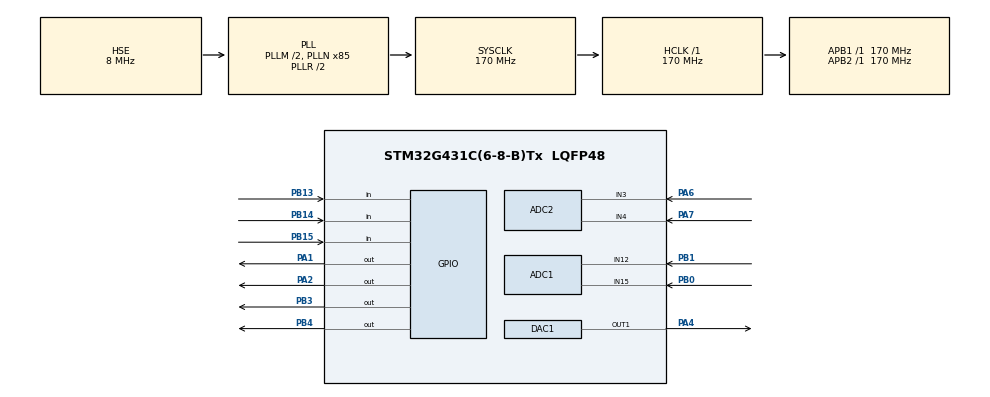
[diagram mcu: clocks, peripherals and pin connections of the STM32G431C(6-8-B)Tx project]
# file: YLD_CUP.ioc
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ADC1.Channel-1\#ChannelRegularConversion=ADC_CHANNEL_15
ADC1.ClockPrescaler=ADC_CLOCK_ASYNC_DIV8
ADC1.NbrOfConversionFlag=1
ADC1.OffsetNumber-1\#ChannelRegularConversion=ADC_OFFSET_NONE
ADC1.Rank-1\#ChannelRegularConversion=1
ADC1.SamplingTime-1\#ChannelRegularConversion=ADC_SAMPLETIME_640CYCLES_5
ADC1.master=1
ADC2.Channel-1\#ChannelRegularConversion=ADC_CHANNEL_3
ADC2.ClockPrescaler=ADC_CLOCK_ASYNC_DIV8
ADC2.NbrOfConversionFlag=1
ADC2.OffsetNumber-1\#ChannelRegularConversion=ADC_OFFSET_NONE
ADC2.Rank-1\#ChannelRegularConversion=1
ADC2.SamplingTime-1\#ChannelRegularConversion=ADC_SAMPLETIME_640CYCLES_5
Mcu.Family=STM32G4
Mcu.Name=STM32G431C(6-8-B)Tx
Mcu.Package=LQFP48
NVIC.PriorityGroup=NVIC_PRIORITYGROUP_4
PA1.Signal=GPIO_Output
PA13.Mode=Serial_Wire
PA13.Signal=SYS_JTMS-SWDIO
PA14.Mode=Serial_Wire
PA14.Signal=SYS_JTCK-SWCLK
PA2.Signal=GPIO_Output
PA4.Signal=COMP_DAC11_group
PA6.Mode=IN3-Single-Ended
PA6.Signal=ADC2_IN3
PA7.Mode=IN4-Single-Ended
PA7.Signal=ADC2_IN4
PB0.Mode=IN15-Single-Ended
PB0.Signal=ADC1_IN15
PB1.Mode=IN12-Single-Ended
PB1.Signal=ADC1_IN12
PB13.GPIO_PuPd=GPIO_PULLUP
PB13.Signal=GPIO_Input
PB14.GPIO_PuPd=GPIO_PULLUP
PB14.Signal=GPIO_Input
PB15.GPIO_PuPd=GPIO_PULLUP
PB15.Signal=GPIO_Input
PB3.GPIO_ModeDefaultOutputPP=GPIO_MODE_OUTPUT_OD
PB3.GPIO_PuPd=GPIO_NOPULL
PB3.GPIO_Speed=GPIO_SPEED_FREQ_HIGH
PB3.PinState=GPIO_PIN_SET
PB3.Signal=GPIO_Output
PB4.GPIO_ModeDefaultOutputPP=GPIO_MODE_OUTPUT_OD
PB4.GPIO_PuPd=GPIO_NOPULL
PB4.GPIO_Speed=GPIO_SPEED_FREQ_HIGH
PB4.PinState=GPIO_PIN_SET
PB4.Signal=GPIO_Output
PF0-OSC_IN.Mode=HSE-External-Oscillator
PF0-OSC_IN.Signal=RCC_OSC_IN
PF1-OSC_OUT.Mode=HSE-External-Oscillator
PF1-OSC_OUT.Signal=RCC_OSC_OUT
ProjectManager.HeapSize=0x200
ProjectManager.StackSize=0x400
ProjectManager.TargetToolchain=CMake
RCC.ADC12Freq_Value=170000000
RCC.AHBFreq_Value=170000000
RCC.APB1Freq_Value=170000000
RCC.APB1TimFreq_Value=170000000
RCC.APB2Freq_Value=170000000
RCC.APB2TimFreq_Value=170000000
RCC.CortexFreq_Value=170000000
RCC.EXTERNAL_CLOCK_VALUE=12288000
RCC.HCLKFreq_Value=170000000
RCC.HSI48_VALUE=48000000
RCC.HSI_VALUE=16000000
RCC.LSE_VALUE=32768
RCC.PLLM=RCC_PLLM_DIV2
RCC.PLLN=85
RCC.PLLSourceVirtual=RCC_PLLSOURCE_HSE
RCC.SYSCLKFreq_VALUE=170000000
RCC.SYSCLKSource=RCC_SYSCLKSOURCE_PLLCLK
RCC.USBFreq_Value=170000000
RCC.VCOOutputFreq_Value=340000000
SH.COMP_DAC11_group.0=DAC1_OUT1,DAC_OUT1
VP_SYS_VS_DBSignals.Mode=DisableDeadBatterySignals
board=custom

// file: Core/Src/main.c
/* USER CODE BEGIN Header */
/**
  ******************************************************************************
  * @file           : main.c
  * @brief          : Main program body
  ******************************************************************************
  * @attention
  *
  * Copyright (c) 2026 STMicroelectronics.
  * All rights reserved.
  *
  * This software is licensed under terms that can be found in the LICENSE file
  * in the root directory of this software component.
  * If no LICENSE file comes with this software, it is provided AS-IS.
  *
  ******************************************************************************
  */
/* USER CODE END Header */
#include "main.h"

/* USER CODE BEGIN Includes */
#include "OLED.h"
#include "buzzer.h"
#include "measurement_calibration.h"
#include <math.h>
/* USER CODE END Includes */

/* USER CODE BEGIN PTD */
/* 应用状态机 (题目 1.1 / 1.2 / 2.1 + 恒流模式) */
typedef enum
{
  APP_ST_SELF_TEST = 0,   /* 开机自检 (蜂鸣 3 声) */
  APP_ST_STANDBY,         /* 待机: 无输出 */
  APP_ST_CV,              /* 恒压模式 */
  APP_ST_CC,              /* 恒流模式 */
  APP_ST_PROT_OCP,        /* 过流保护: 关输出 + 报警, 手动解除 */
  APP_ST_PROT_UVP,        /* 欠压保护: 关输出 + 报警, 手动忽略后恢复 */
  APP_ST_PROT_ADC,        /* 采样故障: 关输出 + 报警, 手动重试后回待机 */
} AppState_t;

/* 按键事件 */
typedef enum
{
  KEY_EV_NONE = 0,
  KEY_EV_SHORT,           /* 短按 (松手时产生) */
  KEY_EV_LONG,            /* 长按 (按住超过 KEY_LONG_MS, 只产生一次) */
} KeyEvent_t;

/* 按键对象 */
typedef struct
{
  GPIO_TypeDef *port;
  uint16_t      pin;
  uint8_t       stable;     /* 消抖后的稳定电平: 1=松开, 0=按下 */
  uint8_t       rawLast;    /* 上一次原始电平 */
  uint32_t      changedAt;  /* 原始电平改变的时刻 */
  uint32_t      pressedAt;  /* 消抖确认按下的时刻 */
  uint8_t       longFired;  /* 已产生过长按事件 */
  KeyEvent_t    event;      /* 本次扫描产生的事件 */
} Key_t;
/* USER CODE END PTD */

/* USER CODE BEGIN PD */
/* ============================================================================
 * 应用层运行参数集中在这里; 实测系数见 measurement_calibration.h
 * ==========================================================================*/

/* ---- ADC 基础参数 ---- */
/* ADC 参考电压: VREF+ 接 VDDA, 本板为 3.3V */
#define ADC_VREF             3.3f
/* 12 位 ADC 满量程值 */
#define ADC_FULL_SCALE       4095.0f
/* 2026-10-20 原理图: 60kΩ/10kΩ 分压, 节点对地 100nF.
   保留 640.5 周期与切换后弃样, ADC 时钟 170/8=21.25MHz;
   单次采样约 30us, 一个通道含弃样及 4 次均值至少约 150us. */
#define ADC_SAMPLING_TIME    ADC_SAMPLETIME_640CYCLES_5
/* 每个通道的过采样次数, 用于简单均值滤波 */
#define ADC_OVERSAMPLING     4U
/* 单次转换的等待超时, 单位 ms */
#define ADC_TIMEOUT_MS       10U

/* ---- 采样调度: "电压组 / 电流组"的时间占比 (任意正整数, 表示相对比例) ----
 * 恒压模式把更多采样时间给电压, 恒流模式把更多给电流.
 * 例如 4:1 = 每 4+1 个循环拍里, 4 拍采电压组 (Vin/Vout), 1 拍采电流组 (Iin/Iout);
 * 想改占比直接改这四个数 (例如 9:1), 两边都配 0 时退化为只采电压组 */
#define CV_VOLT_SLOTS        4U    /* 恒压模式: 电压组时隙数 */
#define CV_CURR_SLOTS        1U    /* 恒压模式: 电流组时隙数 */
#define CC_VOLT_SLOTS        1U    /* 恒流模式: 电压组时隙数 */
#define CC_CURR_SLOTS        4U    /* 恒流模式: 电流组时隙数 */

/* ---- V2.08 实测校准: 系数与函数统一在 measurement_calibration.h ----
 * 电流: 20mΩ × INA199A1 50 倍的名义电流, 再做二次校正;
 * 输出电压: 分压名义值 + 电流相关修正, 估算带载端子电压.
 * 输入参考表接在 D4 前、PA7 接 D4 后, 不把二极管压降当 ADC 误差.
 * 原始数据、拟合与范围见 calibration/README.md; 不做上电自动归零. */
#define VIN_ADC_SCALE        CAL_VIN_ADC_SCALE
#define VOUT_ADC_SCALE       CAL_VOUT_ADC_SCALE

/* ---- DAC: 第二页两步拟合反解见 voltage_calibration.h ----
 * 负载电流用于恒压前馈, 再叠加慢速电压反馈修正; 不保证功率级带载能力. */
#define DAC_VMAX             3.3f    /* DAC 参考电压, 用于码值换算 */
#define DAC_OUTPUT_MIN_V     0.2f    /* 缓冲开启后的规定输出范围 */
#define DAC_OUTPUT_MAX_V     (DAC_VMAX - 0.2f)
#define DAC_FULL_SCALE       4095.0f /* G431 12 位 DAC 满量程码值 */

/* ---- V2.11 恒压小死区纠偏: 只调整 DAC 偏置, 不改写拟合/ADC 系数 ----
 * 负增益通路: Vout 偏低 -> DAC 偏置减小. 仅消费新电压样本,
 * 实际经过时间积分, 带死区、偏置/斜率限幅和抗积分饱和. */
#define CV_TRIM_PERIOD_MS    100U
#define CV_TRIM_SETTLE_MS    400U   /* 合闸或改目标后先等输出稳定 */
#define CV_TRIM_MAX_GAP_MS   500U   /* 长间隔只重建滤波, 不补积历史误差 */
#define CV_TRIM_FILTER_S     0.5f
#define CV_TRIM_DEADBAND_V   0.003f /* 3mV: 小幅掉压也开始纠偏 */
#define CV_TRIM_KI           0.020f /* DAC V / (输出误差 V * s) */
#define CV_TRIM_RATE_V_S     0.005f /* 仅慢速偏置的变化率, DAC V/s */
#define CV_TRIM_MAX_DAC_V    0.100f /* 相对实测前馈的最大 DAC 偏置 */
#define CV_TRIM_MAX_ERROR_V  1.0f   /* 大幅掉压时冻结纠偏, 不持续追高输出 */

/* ---- V2.13 恒流: 大偏差快调, 进入目标附近后慢调; 单位均为 DAC V ----
 * 直接积分实际施加的 DAC 命令, 限幅后不积攒隐藏误差; 无微分放大噪声.
 * CC_FINE_ENTER_A < CC_FINE_EXIT_A 构成迟滞, 避免快慢档来回切换. */
#define CC_CONTROL_PERIOD_MS 10U
#define CC_CONTROL_MAX_GAP_MS 250U /* 超时重建滤波, 不补积历史误差 */
#define CC_CURRENT_FILTER_S  0.030f
#define CC_DEADBAND_A        0.005f
#define CC_FINE_ENTER_A      0.030f
#define CC_FINE_EXIT_A       0.080f
#define CC_FAST_KI           0.800f /* DAC V / (A * s), 待台架整定 */
#define CC_FINE_KI           0.300f
#define CC_FAST_RATE_V_S     0.500f
#define CC_FINE_RATE_V_S     0.030f
#define CC_VOLTAGE_LIMIT_V   VOUT_TARGET_MAX /* 恒流允许的最高输出电压 */
#define CC_VOLTAGE_MARGIN_V  0.050f
#define CC_VOLTAGE_KI        0.200f /* 达到电压上限后只允许降压 */

/* ---- 运行目标与步进 (题目 1.2 / 2.2 / 恒流模式) ---- */
#define VOUT_TARGET_DEFAULT  8.0f    /* 恒压模式默认目标电压 */
#define VOUT_TARGET_MIN      5.0f    /* 步进调压下限 */
#define VOUT_TARGET_MAX      15.0f   /* 步进调压上限 */
#define VOUT_STEP            1.0f    /* 步进 1V */
#define IOUT_TARGET_DEFAULT  1.0f    /* 恒流模式默认目标电流 */
#define IOUT_TARGET_MIN      0.2f
#define IOUT_TARGET_MAX      2.0f
#define IOUT_STEP            0.1f

/* ---- 保护阈值 (题目 2.1) ---- */
#define OCP_TRIP_A           2.3f    /* Iout 超过 -> 过流保护 (手动解除) */
#define OCP_CONFIRM_MS       50U     /* 过流需"持续"该时长才锁存保护, 防负载瞬变误触发 */
#define UVP_TRIP_V           12.5f   /* Vin 持续低于 -> 欠压保护 (手动忽略) */
#define UVP_CONFIRM_MS       3000U   /* 运行中欠压需连续确认 3 秒, 正常样本清零计时 */
#define UVP_RECOVER_V        13.0f   /* 新样本达到该值 -> 结束忽略, 重新启用欠压保护 */
#define PROT_BLANK_MS        300U    /* 合闸后的过流屏蔽期; 欠压/ADC 故障不屏蔽 */

/* ---- 时序 ---- */
#define APP_LOOP_PERIOD_MS   10U     /* 主循环节拍 */
#define DISPLAY_REFRESH_MS   100U    /* 屏幕刷新周期 */
#define DISPLAY_AVG_TICKS    3U      /* 显示平均窗口: 最近 3 次刷新 (约 300ms) */
#define KEY_DEBOUNCE_MS      20U     /* 按键消抖时间 */
#define KEY_LONG_MS          800U    /* 长按判定时间 */
#define BEEP_ON_MS           200U    /* 开机蜂鸣: 每声时长 */
#define BEEP_GAP_MS          500U    /* 开机蜂鸣: 两声间隔 (题目 1.1) */
#define BEEP_STARTUP_TIMES   3U      /* 开机蜂鸣次数 */

/* ---- 按键: 新图 K1=PB15 升, K2=PB14 降, K3=PB13 功能; 按下=低 ---- */
#define KEY_PORT             GPIOB
#define KEY_UP_PIN           GPIO_PIN_15
#define KEY_DOWN_PIN         GPIO_PIN_14
#define KEY_FUNC_PIN         GPIO_PIN_13
#define KEY_IDX_UP           0U
#define KEY_IDX_DOWN         1U
#define KEY_IDX_FUNC         2U

/* ---- OLED 布局 (6×8 字体; 行距 8px) ---- */
#define OLED_FONT            OLED_6X8
/* 数值列 x: 标签区最宽 4 字符 (24px) + 12px 间隙 */
#define OLED_VALUE_X         36U
#define OLED_FLOAT_INT_LEN   2U
#define OLED_FLOAT_FRA_LEN   2U
/* 单位列 x: 数值最宽 "+15.00" 6 字符 = 36px, 后留 6px */
#define OLED_UNIT_X          78U
/* USER CODE END PD */

ADC_HandleTypeDef hadc1;
ADC_HandleTypeDef hadc2;

DAC_HandleTypeDef hdac1;

/* USER CODE BEGIN PV */
/* 引脚 -> 通道 (以 2026-10-20 G431 原理图为准, 旧使用手册不适用):
 *   PA7 = INA_V_IN  (输入电压 ÷7),  PA6 = INA_V_OUT (输出电压 ÷7)   -> ADC2
 *   PB1 = 输入电流,                  PB0 = 输出电流                   -> ADC1
 * 输出通断 MOS: PA1 (高=导通);  无源蜂鸣器: PA2 (TIM2_CH3 PWM)
 * 按键: PB15=K1 升, PB14=K2 降, PB13=K3 功能键 (上拉输入, 按下=低) */
/* DAC: PA4 = DAC1_OUT1, VREF=3.3V */

/* ---- 状态机 ---- */
static AppState_t appState = APP_ST_SELF_TEST;
static AppState_t stateBeforeProtect = APP_ST_CV;  /* 保护前的运行模式, 恢复用 */
static uint32_t   protBlankUntil = 0U;             /* 合闸屏蔽期截止时刻 */
static uint8_t    vinFresh = 0U;                   /* 有新的电压采样 (供欠压确认窗口消费) */
static uint8_t    uvpTracking = 0U;                /* 正在累计连续欠压时间 */
static uint32_t   uvpSince = 0U;                   /* 本轮连续欠压的起始时刻 */
static uint8_t    uvpIgnored = 0U;                 /* 忽略本次欠压, 新样本恢复到 13V 才清除 */
static uint8_t    ioutFresh = 0U;                  /* 有新的电流采样 (供过流确认窗口消费) */
static uint8_t    ocpTracking = 0U;                /* 正在累计过流持续时间 */
static uint32_t   ocpSince = 0U;                   /* 本轮连续过流的起始时刻 */

/* ---- 设定值 ---- */
static float targetV = VOUT_TARGET_DEFAULT;
static float targetI = IOUT_TARGET_DEFAULT;

/* ---- 测量值 (已按标定系数换算) ---- */
static float measVin  = 0.0f;
static float measVout = 0.0f;
static float measVoutNominal = 0.0f; /* PA6 名义电压, 避免电流刷新时重复校正 */
static float measIin  = 0.0f;
static float measIout = 0.0f;
static float dacAppliedV = DAC_OUTPUT_MAX_V; /* 最近成功写入的量化 DAC 电压 */

/* ---- 恒压在线纠偏: RAM 状态, 待机/保护/模式或目标改变时重置 ---- */
static float cvTrimDacV = 0.0f;
static float cvFilteredVout = 0.0f;
static uint32_t cvStartedTick = 0U;
static uint32_t cvLastControlTick = 0U;
static uint32_t voltageSampleTick = 0U; /* CV / CC 共用的采样完成时刻 */
static uint32_t currentSampleTick = 0U;
static uint8_t cvVoltageFresh = 0U; /* 独立于保护消费的 vinFresh */
static uint8_t cvFilterReady = 0U;
static uint8_t cvTrimLimited = 0U;  /* Watch: 偏置达到限幅, 需排查台架 */

/* ---- 恒流闭环: 与保护独立消费电流样本; ccDacV 保留亚码值修正 ---- */
static float ccDacV = DAC_OUTPUT_MAX_V;
static float ccFilteredIout = 0.0f;
static uint32_t ccLastControlTick = 0U;
static uint8_t ccCurrentFresh = 0U;
static uint8_t ccFilterReady = 0U;
static uint8_t ccFineControl = 0U;  /* Watch: 0=快速逼近, 1=稳态微调 */
static uint8_t ccLimited = 0U;      /* Watch: 达到 DAC / 电压上限 */

/* ---- 按键 (K1 / K2 / K3) ---- */
static Key_t keys[3] =
{
  { .port = KEY_PORT, .pin = KEY_UP_PIN,   .stable = 1U, .rawLast = 1U },
  { .port = KEY_PORT, .pin = KEY_DOWN_PIN, .stable = 1U, .rawLast = 1U },
  { .port = KEY_PORT, .pin = KEY_FUNC_PIN, .stable = 1U, .rawLast = 1U },
};

/* ---- 循环节拍 ---- */
static uint32_t lastDisplayTick = 0U;
/* ---- 显示平滑窗口 (行: Vin / Vout / Iin / Iout) ---- */
static float   dispHist[4][DISPLAY_AVG_TICKS];
static uint8_t dispHistIdx = 0U;
static uint8_t dispHistFilled = 0U;
/* USER CODE END PV */

void SystemClock_Config(void);
static void MX_GPIO_Init(void);
static void MX_ADC2_Init(void);
static void MX_DAC1_Init(void);
static void MX_ADC1_Init(void);
/* USER CODE BEGIN PFP */
static uint8_t ADC_ReadVoltage(ADC_HandleTypeDef *hadc, uint32_t channel, float *voltage);

/* 应用层函数 */
static void  App_SetState(AppState_t next);
static void  App_OutputEnable(uint8_t on);
static void  App_Buzzer(uint8_t on);
static void  App_PlayStartupBeeps(void);
static uint8_t App_SampleVoltageGroup(void);
static uint8_t App_SampleCurrentGroup(void);
static void  App_AdcFault(void);
static void  App_SampleScheduler(void);
static void  App_ScanKeys(void);
static void  App_HandleKeyEvent(uint8_t idx, KeyEvent_t ev);
static void  App_CvReset(void);
static void  App_CcReset(void);
static void  App_CcControlStep(void);
static void  App_ControlStep(void);
static void  App_ProtectionCheck(void);
static void  App_UpdateDisplay(void);
static void  App_DisplayAverage(float *vin, float *vout, float *iin, float *iout);
static float App_TargetToDac(float vout);
static void  App_DacSetVoltage(float voltage);
static float App_Clamp(float v, float lo, float hi);
static char *App_StateText(AppState_t st);
/* USER CODE END PFP */

int main(void)
{

  /* MCU Configuration--------------------------------------------------------*/

  /* Reset of all peripherals, Initializes the Flash interface and the Systick. */
  HAL_Init();

  /* Configure the system clock */
  SystemClock_Config();

  /* Initialize all configured peripherals */
  MX_GPIO_Init();
  MX_ADC2_Init();
  MX_DAC1_Init();
  MX_ADC1_Init();
  /* USER CODE BEGIN 2 */
  if (Buzzer_Init() != HAL_OK)
  {
    Error_Handler();
  }
  /* ---- OLED: 软件 I2C, SCL=PB3, SDA=PB4, 内部含清屏 ---- */
  OLED_Init();

  /* 输出 MOS 默认关断 (上电即待机无输出, 题目 1.1), 显式再关一次双保险 */
  App_OutputEnable(0U);
  App_Buzzer(0U);
  App_UpdateDisplay();                 /* 先显示 "Power Manager" + SELF TEST */

  /* ---- DAC1: PA4, 12 位, 参考 3.3V ---- */
  if (HAL_DAC_Start(&hdac1, DAC_CHANNEL_1) != HAL_OK)
  {
    Error_Handler();
  }
  /* 按实测模型预置 8V; 开机尚无负载电流, 先按 0A 外推值设置. */
  App_DacSetVoltage(App_TargetToDac(VOUT_TARGET_DEFAULT));

  /* ADC 校准: 上电后各执行一次, 可消除内部电容误差, 提高转换精度 */
  if (HAL_ADCEx_Calibration_Start(&hadc1, ADC_SINGLE_ENDED) != HAL_OK)
  {
    Error_Handler();
  }
  if (HAL_ADCEx_Calibration_Start(&hadc2, ADC_SINGLE_ENDED) != HAL_OK)
  {
    Error_Handler();
  }
  /* 采样失败保留 ADC 故障状态, 不把故障覆盖成待机. */
  if ((App_SampleVoltageGroup() != 0U) && (App_SampleCurrentGroup() != 0U))
  {
    App_UpdateDisplay();
    App_PlayStartupBeeps();
    /* 蜂鸣后重新采集, 避免继续显示启动过程的旧读数. */
    if ((App_SampleVoltageGroup() != 0U) && (App_SampleCurrentGroup() != 0U))
    {
      App_SetState(APP_ST_STANDBY);
    }
  }
  App_UpdateDisplay();
/* USER CODE END 2 */

  /* Infinite loop */
  while (1)
  {

    /* USER CODE BEGIN 3 */
    uint32_t now = HAL_GetTick();

    /* 1. 按键扫描 + 事件分发 (K1/K2/K3 分工见 App_HandleKeyEvent 注释) */
    App_ScanKeys();
    for (uint8_t i = 0U; i < 3U; i++)
    {
      if (keys[i].event != KEY_EV_NONE)
      {
        App_HandleKeyEvent(i, keys[i].event);
      }
    }

    /* 2. 采样调度: 按当前模式的"电压/电流时间占比"轮流采两组信号 */
    App_SampleScheduler();

    /* 3. 先检查保护, 再允许本拍的控制更新 DAC */
    App_ProtectionCheck();

    /* 4. 恒压前馈及慢速纠偏 / 恒流快调与稳态微调 */
    App_ControlStep();

    /* 5. 显示刷新 (固定周期, 不用每拍都刷) */
    if ((now - lastDisplayTick) >= DISPLAY_REFRESH_MS)
    {
      lastDisplayTick = now;
      App_UpdateDisplay();
    }

    /* 6. 主循环节拍 */
    HAL_Delay(APP_LOOP_PERIOD_MS);
  }
  /* USER CODE END 3 */
}

void SystemClock_Config(void)
{
  RCC_OscInitTypeDef RCC_OscInitStruct = {0};
  RCC_ClkInitTypeDef RCC_ClkInitStruct = {0};

  /** Configure the main internal regulator output voltage
  */
  HAL_PWREx_ControlVoltageScaling(PWR_REGULATOR_VOLTAGE_SCALE1_BOOST);

  /** Initializes the RCC Oscillators according to the specified parameters
  * in the RCC_OscInitTypeDef structure.
  */
  RCC_OscInitStruct.OscillatorType = RCC_OSCILLATORTYPE_HSE;
  RCC_OscInitStruct.HSEState = RCC_HSE_ON;
  RCC_OscInitStruct.PLL.PLLState = RCC_PLL_ON;
  RCC_OscInitStruct.PLL.PLLSource = RCC_PLLSOURCE_HSE;
  RCC_OscInitStruct.PLL.PLLM = RCC_PLLM_DIV2;
  RCC_OscInitStruct.PLL.PLLN = 85;
  RCC_OscInitStruct.PLL.PLLP = RCC_PLLP_DIV2;
  RCC_OscInitStruct.PLL.PLLQ = RCC_PLLQ_DIV2;
  RCC_OscInitStruct.PLL.PLLR = RCC_PLLR_DIV2;
  if (HAL_RCC_OscConfig(&RCC_OscInitStruct) != HAL_OK)
  {
    Error_Handler();
  }

  /** Initializes the CPU, AHB and APB buses clocks
  */
  RCC_ClkInitStruct.ClockType = RCC_CLOCKTYPE_HCLK|RCC_CLOCKTYPE_SYSCLK
                              |RCC_CLOCKTYPE_PCLK1|RCC_CLOCKTYPE_PCLK2;
  RCC_ClkInitStruct.SYSCLKSource = RCC_SYSCLKSOURCE_PLLCLK;
  RCC_ClkInitStruct.AHBCLKDivider = RCC_SYSCLK_DIV1;
  RCC_ClkInitStruct.APB1CLKDivider = RCC_HCLK_DIV1;
  RCC_ClkInitStruct.APB2CLKDivider = RCC_HCLK_DIV1;

  if (HAL_RCC_ClockConfig(&RCC_ClkInitStruct, FLASH_LATENCY_4) != HAL_OK)
  {
    Error_Handler();
  }
}

static void MX_ADC1_Init(void)
{

  ADC_MultiModeTypeDef multimode = {0};
  ADC_ChannelConfTypeDef sConfig = {0};

  /** Common config
  */
  hadc1.Instance = ADC1;
  hadc1.Init.ClockPrescaler = ADC_CLOCK_ASYNC_DIV8;
  hadc1.Init.Resolution = ADC_RESOLUTION_12B;
  hadc1.Init.DataAlign = ADC_DATAALIGN_RIGHT;
  hadc1.Init.GainCompensation = 0;
  hadc1.Init.ScanConvMode = ADC_SCAN_DISABLE;
  hadc1.Init.EOCSelection = ADC_EOC_SINGLE_CONV;
  hadc1.Init.LowPowerAutoWait = DISABLE;
  hadc1.Init.ContinuousConvMode = DISABLE;
  hadc1.Init.NbrOfConversion = 1;
  hadc1.Init.DiscontinuousConvMode = DISABLE;
  hadc1.Init.ExternalTrigConv = ADC_SOFTWARE_START;
  hadc1.Init.ExternalTrigConvEdge = ADC_EXTERNALTRIGCONVEDGE_NONE;
  hadc1.Init.DMAContinuousRequests = DISABLE;
  hadc1.Init.Overrun = ADC_OVR_DATA_PRESERVED;
  hadc1.Init.OversamplingMode = DISABLE;
  if (HAL_ADC_Init(&hadc1) != HAL_OK)
  {
    Error_Handler();
  }

  /** Configure the ADC multi-mode
  */
  multimode.Mode = ADC_MODE_INDEPENDENT;
  if (HAL_ADCEx_MultiModeConfigChannel(&hadc1, &multimode) != HAL_OK)
  {
    Error_Handler();
  }

  /** Configure Regular Channel
  */
  sConfig.Channel = ADC_CHANNEL_15;
  sConfig.Rank = ADC_REGULAR_RANK_1;
  sConfig.SamplingTime = ADC_SAMPLETIME_640CYCLES_5;
  sConfig.SingleDiff = ADC_SINGLE_ENDED;
  sConfig.OffsetNumber = ADC_OFFSET_NONE;
  sConfig.Offset = 0;
  if (HAL_ADC_ConfigChannel(&hadc1, &sConfig) != HAL_OK)
  {
    Error_Handler();
  }

}

static void MX_ADC2_Init(void)
{

  ADC_ChannelConfTypeDef sConfig = {0};

  /** Common config
  */
  hadc2.Instance = ADC2;
  hadc2.Init.ClockPrescaler = ADC_CLOCK_ASYNC_DIV8;
  hadc2.Init.Resolution = ADC_RESOLUTION_12B;
  hadc2.Init.DataAlign = ADC_DATAALIGN_RIGHT;
  hadc2.Init.GainCompensation = 0;
  hadc2.Init.ScanConvMode = ADC_SCAN_DISABLE;
  hadc2.Init.EOCSelection = ADC_EOC_SINGLE_CONV;
  hadc2.Init.LowPowerAutoWait = DISABLE;
  hadc2.Init.ContinuousConvMode = DISABLE;
  hadc2.Init.NbrOfConversion = 1;
  hadc2.Init.DiscontinuousConvMode = DISABLE;
  hadc2.Init.ExternalTrigConv = ADC_SOFTWARE_START;
  hadc2.Init.ExternalTrigConvEdge = ADC_EXTERNALTRIGCONVEDGE_NONE;
  hadc2.Init.DMAContinuousRequests = DISABLE;
  hadc2.Init.Overrun = ADC_OVR_DATA_PRESERVED;
  hadc2.Init.OversamplingMode = DISABLE;
  if (HAL_ADC_Init(&hadc2) != HAL_OK)
  {
    Error_Handler();
  }

  /** Configure Regular Channel
  */
  sConfig.Channel = ADC_CHANNEL_3;
  sConfig.Rank = ADC_REGULAR_RANK_1;
  sConfig.SamplingTime = ADC_SAMPLETIME_640CYCLES_5;
  sConfig.SingleDiff = ADC_SINGLE_ENDED;
  sConfig.OffsetNumber = ADC_OFFSET_NONE;
  sConfig.Offset = 0;
  if (HAL_ADC_ConfigChannel(&hadc2, &sConfig) != HAL_OK)
  {
    Error_Handler();
  }

}

static void MX_DAC1_Init(void)
{

  DAC_ChannelConfTypeDef sConfig = {0};

  /** DAC Initialization
  */
  hdac1.Instance = DAC1;
  if (HAL_DAC_Init(&hdac1) != HAL_OK)
  {
    Error_Handler();
  }

  /** DAC channel OUT1 config
  */
  sConfig.DAC_HighFrequency = DAC_HIGH_FREQUENCY_INTERFACE_MODE_AUTOMATIC;
  sConfig.DAC_DMADoubleDataMode = DISABLE;
  sConfig.DAC_SignedFormat = DISABLE;
  sConfig.DAC_SampleAndHold = DAC_SAMPLEANDHOLD_DISABLE;
  sConfig.DAC_Trigger = DAC_TRIGGER_NONE;
  sConfig.DAC_Trigger2 = DAC_TRIGGER_NONE;
  sConfig.DAC_OutputBuffer = DAC_OUTPUTBUFFER_ENABLE;
  sConfig.DAC_ConnectOnChipPeripheral = DAC_CHIPCONNECT_EXTERNAL;
  sConfig.DAC_UserTrimming = DAC_TRIMMING_FACTORY;
  if (HAL_DAC_ConfigChannel(&hdac1, &sConfig, DAC_CHANNEL_1) != HAL_OK)
  {
    Error_Handler();
  }

}

static void MX_GPIO_Init(void)
{
  GPIO_InitTypeDef GPIO_InitStruct = {0};

  /* GPIO Ports Clock Enable */
  __HAL_RCC_GPIOF_CLK_ENABLE();
  __HAL_RCC_GPIOA_CLK_ENABLE();
  __HAL_RCC_GPIOB_CLK_ENABLE();

  /*Configure GPIO pin Output Level */
  HAL_GPIO_WritePin(GPIOA, GPIO_PIN_1|GPIO_PIN_2, GPIO_PIN_RESET);

  /*Configure GPIO pin Output Level */
  HAL_GPIO_WritePin(GPIOB, GPIO_PIN_3|GPIO_PIN_4, GPIO_PIN_SET);

  /*Configure GPIO pins : PA1 PA2 */
  GPIO_InitStruct.Pin = GPIO_PIN_1|GPIO_PIN_2;
  GPIO_InitStruct.Mode = GPIO_MODE_OUTPUT_PP;
  GPIO_InitStruct.Pull = GPIO_NOPULL;
  GPIO_InitStruct.Speed = GPIO_SPEED_FREQ_LOW;
  HAL_GPIO_Init(GPIOA, &GPIO_InitStruct);

  /*Configure GPIO pins : PB11 PB9 */
  GPIO_InitStruct.Pin = GPIO_PIN_11|GPIO_PIN_9;
  GPIO_InitStruct.Mode = GPIO_MODE_INPUT;
  GPIO_InitStruct.Pull = GPIO_PULLUP;
  HAL_GPIO_Init(GPIOB, &GPIO_InitStruct);

  /*Configure GPIO pin : PA8 */
  GPIO_InitStruct.Pin = GPIO_PIN_8;
  GPIO_InitStruct.Mode = GPIO_MODE_INPUT;
  GPIO_InitStruct.Pull = GPIO_PULLUP;
  HAL_GPIO_Init(GPIOA, &GPIO_InitStruct);

  /*Configure GPIO pins : PB3 PB4 */
  GPIO_InitStruct.Pin = GPIO_PIN_3|GPIO_PIN_4;
  GPIO_InitStruct.Mode = GPIO_MODE_OUTPUT_OD;
  GPIO_InitStruct.Pull = GPIO_NOPULL;
  GPIO_InitStruct.Speed = GPIO_SPEED_FREQ_HIGH;
  HAL_GPIO_Init(GPIOB, &GPIO_InitStruct);

  /* USER CODE BEGIN MX_GPIO_Init_2 */
  /* 新图按键迁至 PB13/PB14/PB15; 与 .ioc 同步, 写在用户区以便重新生成保留.
     旧生成区的 PA8/PB9/PB11 已不接按键, 将它们恢复为无上下拉模拟输入. */
  GPIO_InitStruct.Pin = GPIO_PIN_8;
  GPIO_InitStruct.Mode = GPIO_MODE_ANALOG;
  GPIO_InitStruct.Pull = GPIO_NOPULL;
  HAL_GPIO_Init(GPIOA, &GPIO_InitStruct);
  GPIO_InitStruct.Pin = GPIO_PIN_9 | GPIO_PIN_11;
  HAL_GPIO_Init(GPIOB, &GPIO_InitStruct);
  GPIO_InitStruct.Pin = KEY_UP_PIN | KEY_DOWN_PIN | KEY_FUNC_PIN;
  GPIO_InitStruct.Mode = GPIO_MODE_INPUT;
  GPIO_InitStruct.Pull = GPIO_PULLUP;
  HAL_GPIO_Init(KEY_PORT, &GPIO_InitStruct);
  /* USER CODE END MX_GPIO_Init_2 */
}

/* USER CODE BEGIN 4 */
/**
  * @brief  读取指定 ADC 的一个通道, 返回该通道的电压值 (已做均值滤波).
  * @note   CubeMX 中 ADC 配置为 "ScanConvMode = Disable, NbrOfConversion = 1",
  *         因此这里在每次转换前把目标通道写入规则组 Rank1, 逐个通道轮流采集,
  *         不需要修改 MX_ADCx_Init() 生成的代码, 也不需要 DMA.
  *         G431 的 ADC 通道是单端/差分可选的, 这里固定用单端.
  * @param  hadc    : ADC 句柄, hadc1 或 hadc2
  * @param  channel : ADC 通道宏, 例如 ADC_CHANNEL_15
  * @param  voltage : 成功时写入 ADC 引脚电压 (V); 失败时不改旧值
  * @retval 1=成功, 0=HAL 错误; 失败不能伪装成零电流
  */
static uint8_t ADC_ReadVoltage(ADC_HandleTypeDef *hadc, uint32_t channel, float *voltage)
{
  ADC_ChannelConfTypeDef sConfig = {0};
  uint32_t sum = 0U;
  uint32_t i;

  /* 停止并关闭 ADC, 保证修改通道配置时 ADC 处于空闲状态 */
  if (HAL_ADC_Stop(hadc) != HAL_OK)
  {
    return 0U;
  }

  /* 把目标通道配置到规则组的第 1 个转换 */
  sConfig.Channel = channel;
  sConfig.Rank = ADC_REGULAR_RANK_1;
  sConfig.SamplingTime = ADC_SAMPLING_TIME;
  sConfig.SingleDiff = ADC_SINGLE_ENDED;
  sConfig.OffsetNumber = ADC_OFFSET_NONE;
  sConfig.Offset = 0U;
  if (HAL_ADC_ConfigChannel(hadc, &sConfig) != HAL_OK)
  {
    return 0U;
  }

  /* 通道刚切换后的第一次转换会受采样保持电容残留电荷影响, 丢弃;
     之后再做 ADC_OVERSAMPLING 次求平均. 高阻分压下这一条对消除串扰很关键 */
  for (i = 0U; i < (ADC_OVERSAMPLING + 1U); i++)
  {
    if (HAL_ADC_Start(hadc) != HAL_OK)
    {
      HAL_ADC_Stop(hadc);
      return 0U;
    }
    if (HAL_ADC_PollForConversion(hadc, ADC_TIMEOUT_MS) != HAL_OK)
    {
      HAL_ADC_Stop(hadc);
      return 0U;
    }
    if (i > 0U)                    /* 丢弃通道切换后的第一个样本 */
    {
      sum += HAL_ADC_GetValue(hadc);
    }
  }

  if (HAL_ADC_Stop(hadc) != HAL_OK)
  {
    return 0U;
  }

  /* 12 位 ADC: V = 码值 / 4095 * VREF */
  *voltage = ((float)sum / (float)ADC_OVERSAMPLING) * ADC_VREF / ADC_FULL_SCALE;
  return 1U;
}

/* --------------------------------------------------------------------------
 * 应用层实现
 * -------------------------------------------------------------------------- */

static float App_Clamp(float v, float lo, float hi)
{
  if (v < lo)
  {
    return lo;
  }
  if (v > hi)
  {
    return hi;
  }
  return v;
}

/* 目标端子电压 + 最新校正电流 -> 两步模型反解 -> PA4 DAC 电压. */
static float App_TargetToDac(float vout)
{
  if (!isfinite(vout) || !isfinite(measIout)) return DAC_OUTPUT_MAX_V;
  return App_Clamp(Cal_TargetToDac(vout, measIout),
                   DAC_OUTPUT_MIN_V, DAC_OUTPUT_MAX_V);
}

/* DAC 电压 -> 12 位码值并写入 DAC1_OUT1 (PA4).
 * 3.3V 对应 4095, 四舍五入; 同时挡住 NaN / 越界, 避免浮点转整数未定义行为 */
static void App_DacSetVoltage(float voltage)
{
  float code;

  /* 负增益通路: 非有限值取高 DAC 电压以降低输出, 不要错误归零推高输出. */
  if (!isfinite(voltage))
  {
    voltage = DAC_OUTPUT_MAX_V;
  }
  voltage = App_Clamp(voltage, DAC_OUTPUT_MIN_V, DAC_OUTPUT_MAX_V);

  code = voltage * DAC_FULL_SCALE / DAC_VMAX + 0.5f;
  if (code >= DAC_FULL_SCALE)
  {
    code = DAC_FULL_SCALE;
  }
  if (HAL_DAC_SetValue(&hdac1, DAC_CHANNEL_1, DAC_ALIGN_12B_R, (uint32_t)code) != HAL_OK)
  {
    Error_Handler();
  }
  dacAppliedV = (float)(uint32_t)code * DAC_VMAX / DAC_FULL_SCALE;
}

/* 输出通断 MOS: PA1 高电平导通 */
static void App_OutputEnable(uint8_t on)
{
  HAL_GPIO_WritePin(GPIOA, GPIO_PIN_1, (on != 0U) ? GPIO_PIN_SET : GPIO_PIN_RESET);
}

/* 无源蜂鸣器：PA2 约 2.4kHz PWM / 低电平静音。 */
static void App_Buzzer(uint8_t on)
{
  Buzzer_Set(on);
}

/* 开机蜂鸣: 响 BEEP_ON_MS, 停 BEEP_GAP_MS, 共 BEEP_STARTUP_TIMES 次 (题目 1.1).
 * 只在启动阶段调用, 阻塞可接受 */
static void App_PlayStartupBeeps(void)
{
  uint8_t i;

  for (i = 0U; i < BEEP_STARTUP_TIMES; i++)
  {
    App_Buzzer(1U);
    HAL_Delay(BEEP_ON_MS);
    App_Buzzer(0U);
    HAL_Delay(BEEP_GAP_MS);
  }
}

/* 采电压组: Vin 保留 D4 后采样; Vout 使用最新电流估算端子电压. */
static uint8_t App_SampleVoltageGroup(void)
{
  float vin;
  float vout;
  if ((ADC_ReadVoltage(&hadc2, ADC_CHANNEL_4, &vin) == 0U) ||
      (ADC_ReadVoltage(&hadc2, ADC_CHANNEL_3, &vout) == 0U))
  {
    App_AdcFault();
    return 0U;
  }
  measVin = vin * VIN_ADC_SCALE;     /* PA7 */
  /* 只用成功的新电压样本结束忽略; 待机、模式切换及其他保护均不清除此标志. */
  if (measVin >= UVP_RECOVER_V)
  {
    uvpIgnored = 0U;
  }
  measVoutNominal = vout * VOUT_ADC_SCALE; /* PA6; 相对系统地 */
  measVout = Cal_Vout(measVoutNominal, measIout);
  voltageSampleTick = HAL_GetTick();
  cvVoltageFresh = 1U;
  vinFresh = 1U;
  return 1U;
}

/* 采电流组: 输入/输出电流 */
static uint8_t App_SampleCurrentGroup(void)
{
  float iin;
  float iout;
  if ((ADC_ReadVoltage(&hadc1, ADC_CHANNEL_12, &iin) == 0U) ||
      (ADC_ReadVoltage(&hadc1, ADC_CHANNEL_15, &iout) == 0U))
  {
    App_AdcFault();
    return 0U;
  }
  measIin = Cal_Iin(iin);
  measIout = Cal_Iout(iout);
  measVout = Cal_Vout(measVoutNominal, measIout);
  currentSampleTick = HAL_GetTick();
  ccCurrentFresh = 1U;         /* 独立于过流保护的 ioutFresh */
  ioutFresh = 1U;               /* 电流数据已刷新, 供过流确认窗口消费 */
  return 1U;
}

static void App_AdcFault(void)
{
  ioutFresh = 0U;
  if (appState != APP_ST_PROT_ADC)
  {
    App_SetState(APP_ST_PROT_ADC);
  }
}

/* 采样调度器: 每个循环拍消费一个"时隙".
 * 恒压模式偏向电压 (CV_VOLT_SLOTS : CV_CURR_SLOTS), 恒流模式偏向电流 (CC_*),
 * 占比宏在文件头部, 想调就改那里 */
static void App_SampleScheduler(void)
{
  static uint8_t slot = 0U;
  uint8_t voltSlots;
  uint8_t currSlots;
  uint8_t total;

  voltSlots = (appState == APP_ST_CC) ? CC_VOLT_SLOTS : CV_VOLT_SLOTS;
  currSlots = (appState == APP_ST_CC) ? CC_CURR_SLOTS : CV_CURR_SLOTS;
  total = (uint8_t)(voltSlots + currSlots);

  if (total == 0U)                 /* 防呆: 宏都配 0 时退化为全采电压 */
  {
    App_SampleVoltageGroup();
    return;
  }
  if (slot >= total)
  {
    slot = 0U;
  }

  if (slot < voltSlots)
  {
    App_SampleVoltageGroup();
  }
  else
  {
    App_SampleCurrentGroup();
  }
  slot++;
}

/* 按键扫描: 上拉输入, 按下=低. 消抖 KEY_DEBOUNCE_MS, 长按 KEY_LONG_MS.
 * 短按在松手时产生; 长按在按住达到阈值时产生一次, 之后松手不再产生短按 */
static void App_ScanKeys(void)
{
  uint32_t now = HAL_GetTick();
  uint8_t i;

  for (i = 0U; i < 3U; i++)
  {
    uint8_t raw = (HAL_GPIO_ReadPin(keys[i].port, keys[i].pin) == GPIO_PIN_RESET) ? 0U : 1U;

    keys[i].event = KEY_EV_NONE;

    if (raw != keys[i].rawLast)
    {
      keys[i].rawLast = raw;
      keys[i].changedAt = now;
    }
    /* 用真实毫秒数消抖/判长按, OLED 刷新和 ADC 耗时不计成固定 10ms. */
    if ((raw != keys[i].stable) &&
        ((uint32_t)(now - keys[i].changedAt) >= KEY_DEBOUNCE_MS))
    {
      keys[i].stable = raw;
      if (raw == 0U)
      {
        keys[i].pressedAt = now;
        keys[i].longFired = 0U;
      }
      else if (keys[i].longFired == 0U)
      {
        keys[i].event = KEY_EV_SHORT;
      }
    }
    if ((raw == 0U) && (keys[i].stable == 0U) && (keys[i].longFired == 0U) &&
        ((uint32_t)(now - keys[i].pressedAt) >= KEY_LONG_MS))
    {
      keys[i].longFired = 1U;
      keys[i].event = KEY_EV_LONG;
    }
  }
}

/* 按键事件分发 —— 按键分工:
 *   待机:      K3 短按 -> 进入恒压 (待机 <-> 恒压 的双向切换键, 题目 1.2)
 *   恒压运行:  K1/K2 短按 -> 目标 ±1V;  K3 短按 -> 回待机;  K3 长按 -> 切恒流
 *   恒流运行:  K1/K2 短按 -> 目标 ±0.1A; K3 短按 -> 回待机; K3 长按 -> 切恒压
 *   过流保护:  K3 短按 -> 解除, 回保护前模式 (合闸前统一检查采样及未忽略的欠压)
 *   欠压保护:  K3 短按 -> 忽略并回保护前模式; Vin 恢复到 13V 前不重复欠压告警
 * TODO: K1/K2 长按连发 (快速调节), 后续再加 */
static void App_HandleKeyEvent(uint8_t idx, KeyEvent_t ev)
{
  if (ev == KEY_EV_NONE)
  {
    return;
  }

  switch (appState)
  {
    case APP_ST_STANDBY:
      if ((idx == KEY_IDX_FUNC) && (ev == KEY_EV_SHORT))
      {
        App_SetState(APP_ST_CV);
      }
      break;

    case APP_ST_CV:
      if ((idx == KEY_IDX_UP) && (ev == KEY_EV_SHORT))
      {
        float next = App_Clamp(targetV + VOUT_STEP, VOUT_TARGET_MIN, VOUT_TARGET_MAX);
        if (next != targetV) { targetV = next; App_CvReset(); }
        App_DacSetVoltage(App_TargetToDac(targetV) + cvTrimDacV);
      }
      else if ((idx == KEY_IDX_DOWN) && (ev == KEY_EV_SHORT))
      {
        float next = App_Clamp(targetV - VOUT_STEP, VOUT_TARGET_MIN, VOUT_TARGET_MAX);
        if (next != targetV) { targetV = next; App_CvReset(); }
        App_DacSetVoltage(App_TargetToDac(targetV) + cvTrimDacV);
      }
      else if (idx == KEY_IDX_FUNC)
      {
        if (ev == KEY_EV_SHORT)
        {
          App_SetState(APP_ST_STANDBY);
        }
        else
        {
          App_SetState(APP_ST_CC);              /* 长按切恒流 */
        }
      }
      else
      {
        /* 其余组合暂不响应 */
      }
      break;

    case APP_ST_CC:
      if ((idx == KEY_IDX_UP) && (ev == KEY_EV_SHORT))
      {
        float next = App_Clamp(targetI + IOUT_STEP, IOUT_TARGET_MIN, IOUT_TARGET_MAX);
        if (next != targetI) { targetI = next; ccFineControl = 0U; }
      }
      else if ((idx == KEY_IDX_DOWN) && (ev == KEY_EV_SHORT))
      {
        float next = App_Clamp(targetI - IOUT_STEP, IOUT_TARGET_MIN, IOUT_TARGET_MAX);
        if (next != targetI) { targetI = next; ccFineControl = 0U; }
      }
      else if (idx == KEY_IDX_FUNC)
      {
        if (ev == KEY_EV_SHORT)
        {
          App_SetState(APP_ST_STANDBY);
        }
        else
        {
          App_SetState(APP_ST_CV);              /* 长按切恒压 */
        }
      }
      else
      {
        /* 其余组合暂不响应 */
      }
      break;

    case APP_ST_PROT_OCP:
      if ((idx == KEY_IDX_FUNC) && (ev == KEY_EV_SHORT))
      {
        App_SetState(stateBeforeProtect);       /* 合闸前统一采样及检查保护 */
      }
      break;

    case APP_ST_PROT_UVP:
      if ((idx == KEY_IDX_FUNC) && (ev == KEY_EV_SHORT))
      {
        uvpIgnored = 1U;                        /* 本次欠压只告警一次, 正常样本重新使能 */
        App_SetState(stateBeforeProtect);       /* 手动忽略后恢复输出, ADC 故障仍可阻止合闸 */
      }
      break;

    case APP_ST_PROT_ADC:
      if ((idx == KEY_IDX_FUNC) && (ev == KEY_EV_SHORT))
      {
        /* 故障恢复后先回待机, 再次按键才合闸; 不能自动恢复功率输出. */
        if ((App_SampleVoltageGroup() != 0U) && (App_SampleCurrentGroup() != 0U))
        {
          App_SetState(APP_ST_STANDBY);
        }
      }
      break;

    default:
      break;
  }
}

/* 状态切换入口: 统一处理"输出通断 / DAC 预置 / 报警 / 屏蔽期"等进入动作 */
static void App_SetState(AppState_t next)
{
  uint8_t wasRunning = (appState == APP_ST_CV || appState == APP_ST_CC) ? 1U : 0U;
  /* 合闸前取得新测量, 不允许拿故障值或过时 Vin 开输出. */
  if ((next == APP_ST_CV) || (next == APP_ST_CC))
  {
    if ((App_SampleVoltageGroup() == 0U) || (App_SampleCurrentGroup() == 0U))
    {
      return;  /* 采样函数已切到 ADC 故障并关断输出 */
    }
    if ((uvpIgnored == 0U) && (measVin < UVP_TRIP_V))
    {
      stateBeforeProtect = next;
      next = APP_ST_PROT_UVP;
    }
  }

  /* 离开运行模式时记下它, 供保护恢复用 */
  if ((appState == APP_ST_CV) || (appState == APP_ST_CC))
  {
    stateBeforeProtect = appState;
  }

  appState = next;
  App_CvReset();
  App_CcReset();

  /* 状态切换后重新确认欠压, 不沿用上次运行的计时或合闸前样本. */
  vinFresh = 0U;
  uvpTracking = 0U;

  /* 状态切换后显示平均窗口重新起算, 避免上一状态的读数混进新状态 */
  dispHistFilled = 0U;
  dispHistIdx = 0U;

  /* 进入运行模式: 过流确认窗口重新起算, 清掉上一段的残留 */
  if ((next == APP_ST_CV) || (next == APP_ST_CC))
  {
    ioutFresh = 0U;
    ocpTracking = 0U;
  }

  switch (next)
  {
    case APP_ST_SELF_TEST:
    case APP_ST_STANDBY:
      App_OutputEnable(0U);                     /* 待机无输出 (题目 1.1) */
      App_Buzzer(0U);
      break;

    case APP_ST_CV:
      targetV = App_Clamp(targetV, VOUT_TARGET_MIN, VOUT_TARGET_MAX);
      App_DacSetVoltage(App_TargetToDac(targetV)); /* 开环预置, 减小合闸过冲 */
      App_OutputEnable(1U);
      App_Buzzer(0U);
      protBlankUntil = HAL_GetTick() + PROT_BLANK_MS;
      break;

    case APP_ST_CC:
      targetI = App_Clamp(targetI, IOUT_TARGET_MIN, IOUT_TARGET_MAX);
      /* 运行中切换跟踪当前实际 DAC; 从待机/保护恢复先预置最低输出档. */
      ccDacV = wasRunning ? App_Clamp(dacAppliedV,
                                     App_TargetToDac(CC_VOLTAGE_LIMIT_V), DAC_OUTPUT_MAX_V)
                          : DAC_OUTPUT_MAX_V;
      App_DacSetVoltage(ccDacV);
      App_OutputEnable(1U);
      App_Buzzer(0U);
      protBlankUntil = HAL_GetTick() + PROT_BLANK_MS;
      break;

    case APP_ST_PROT_OCP:
      App_OutputEnable(0U);                     /* 关输出 */
      App_Buzzer(1U);                           /* 报警 */
      break;

    case APP_ST_PROT_UVP:
    case APP_ST_PROT_ADC:
      App_OutputEnable(0U);
      App_Buzzer(1U);
      break;

    default:
      break;
  }
}

static void App_CvReset(void)
{
  cvTrimDacV = 0.0f;
  cvFilteredVout = 0.0f;
  cvStartedTick = cvLastControlTick = HAL_GetTick();
  cvVoltageFresh = cvFilterReady = cvTrimLimited = 0U;
}

static void App_CcReset(void)
{
  ccDacV = DAC_OUTPUT_MAX_V;
  ccFilteredIout = 0.0f;
  ccLastControlTick = HAL_GetTick();
  ccCurrentFresh = ccFilterReady = ccFineControl = ccLimited = 0U;
}

/* 负增益积分环: 电流不足 -> DAC 下降 -> 输出升高. 快慢档切换保留命令,
 * 只积分新电流样本的真实时间, 不把 OLED 耗时误当成固定 10ms.
 * 直接夹紧命令本身, 无饱和后仍需释放的独立积分项. */
static void App_CcControlStep(void)
{
  uint32_t now, elapsed;
  float lo, dt, error, rawError, ki, rate, step;
  if (!isfinite(targetI) || !isfinite(measIout) || !isfinite(measVin) ||
      !isfinite(measVout) || !isfinite(ccDacV))
  {
    App_AdcFault();
    return;
  }
  if (ccCurrentFresh == 0U) return;
  now = currentSampleTick;
  elapsed = now - ccLastControlTick;
  if (elapsed < CC_CONTROL_PERIOD_MS) return;
  ccCurrentFresh = 0U;
  ccLastControlTick = now;
  lo = App_TargetToDac(CC_VOLTAGE_LIMIT_V);
  ccDacV = App_Clamp(ccDacV, lo, DAC_OUTPUT_MAX_V);
  if (ccFilterReady == 0U || elapsed > CC_CONTROL_MAX_GAP_MS)
  {
    ccFilteredIout = measIout;
    ccFilterReady = 1U;
    ccFineControl = 0U;
    App_DacSetVoltage(ccDacV);
    return; /* 首样本/长间隔只建立滤波, 不追补控制 */
  }
  dt = (float)elapsed * 0.001f;
  ccFilteredIout += dt / (CC_CURRENT_FILTER_S + dt) * (measIout - ccFilteredIout);
  error = targetI - ccFilteredIout;
  rawError = targetI - measIout;
  if (fabsf(error) > CC_FINE_EXIT_A || fabsf(rawError) > CC_FINE_EXIT_A)
    ccFineControl = 0U;
  else if (fabsf(error) <= CC_FINE_ENTER_A && fabsf(rawError) <= CC_FINE_ENTER_A)
    ccFineControl = 1U;
  ki = ccFineControl ? CC_FINE_KI : CC_FAST_KI;
  rate = ccFineControl ? CC_FINE_RATE_V_S : CC_FAST_RATE_V_S;
  if (error > CC_DEADBAND_A) error -= CC_DEADBAND_A;
  else if (error < -CC_DEADBAND_A) error += CC_DEADBAND_A;
  else error = 0.0f;
  step = App_Clamp(-ki * error * dt, -rate * dt, rate * dt);
  /* 滤波的滞后不能让命令在原始电流已到目标时继续向同一方向推动. */
  if ((step < 0.0f && rawError <= CC_DEADBAND_A) ||
      (step > 0.0f && rawError >= -CC_DEADBAND_A)) step = 0.0f;
  /* 电压样本过时/输入欠压/达到电压上限时禁止继续升压, 仍允许降流. */
  if (step < 0.0f && (measVin < UVP_TRIP_V || measVout >= CC_VOLTAGE_LIMIT_V ||
      (uint32_t)(HAL_GetTick() - voltageSampleTick) > CC_CONTROL_MAX_GAP_MS))
    step = 0.0f;
  if ((uint32_t)(HAL_GetTick() - voltageSampleTick) <= CC_CONTROL_MAX_GAP_MS &&
      measVout > CC_VOLTAGE_LIMIT_V + CC_VOLTAGE_MARGIN_V)
    step = fmaxf(step, fminf(CC_FAST_RATE_V_S * dt,
                            CC_VOLTAGE_KI * (measVout - CC_VOLTAGE_LIMIT_V) * dt));
  ccDacV = App_Clamp(ccDacV + step, lo, DAC_OUTPUT_MAX_V);
  ccLimited = (ccDacV <= lo || ccDacV >= DAC_OUTPUT_MAX_V ||
               measVout >= CC_VOLTAGE_LIMIT_V) ? 1U : 0U;
  App_DacSetVoltage(ccDacV);
}

/* 两步实测前馈 + 慢速积分外环. 用输出 ADC 估计电压, 没有采样 FB 引脚.
 * 不按循环次数累加, 不重用旧电压样本; 保护检查在本函数之前执行.
 * CC 在独立分支按新电流样本快慢调节; 独立调参固件不调用本函数. */
static void App_ControlStep(void)
{
  float base, lo, hi;
  if (appState == APP_ST_CC) { App_CcControlStep(); return; }
  if (appState != APP_ST_CV) return;
  if (!isfinite(targetV) || !isfinite(measVout) ||
      !isfinite(measVin) || !isfinite(measIout))
  {
    App_AdcFault();
    return;
  }
  base = App_TargetToDac(targetV);
  lo = fmaxf(-CV_TRIM_MAX_DAC_V, DAC_OUTPUT_MIN_V - base);
  hi = fminf(CV_TRIM_MAX_DAC_V, DAC_OUTPUT_MAX_V - base);
  cvTrimDacV = App_Clamp(cvTrimDacV, lo, hi);

  if (cvVoltageFresh != 0U)
  {
    uint32_t now = voltageSampleTick;
    uint32_t elapsed = now - cvLastControlTick;
    cvVoltageFresh = 0U;
    if ((uint32_t)(now - cvStartedTick) >= CV_TRIM_SETTLE_MS &&
        elapsed >= CV_TRIM_PERIOD_MS)
    {
      cvLastControlTick = now;
      if (cvFilterReady == 0U || elapsed > CV_TRIM_MAX_GAP_MS)
      {
        cvFilteredVout = measVout;
        cvFilterReady = 1U;
      }
      else
      {
        float dt = (float)elapsed * 0.001f;
        float error;
        cvFilteredVout += dt / (CV_TRIM_FILTER_S + dt) * (measVout - cvFilteredVout);
        error = targetV - cvFilteredVout;
        if ((uint32_t)(HAL_GetTick() - currentSampleTick) <= CV_TRIM_MAX_GAP_MS &&
            measVin >= UVP_TRIP_V && measIout <= OCP_TRIP_A &&
            fabsf(targetV - measVout) <= CV_TRIM_MAX_ERROR_V &&
            fabsf(error) <= CV_TRIM_MAX_ERROR_V)
        {
          float step;
          if (error > CV_TRIM_DEADBAND_V) error -= CV_TRIM_DEADBAND_V;
          else if (error < -CV_TRIM_DEADBAND_V) error += CV_TRIM_DEADBAND_V;
          else error = 0.0f;
          step = App_Clamp(-CV_TRIM_KI * error * dt,
                           -CV_TRIM_RATE_V_S * dt, CV_TRIM_RATE_V_S * dt);
          /* 直接夹紧实际施加的积分偏置, 饱和时不积攒隐藏误差. */
          cvTrimDacV = App_Clamp(cvTrimDacV + step, lo, hi);
        }
      }
    }
  }
  cvTrimLimited = (cvTrimDacV <= lo || cvTrimDacV >= hi) ? 1U : 0U;
  App_DacSetVoltage(base + cvTrimDacV);
}

/* 保护检查 (题目 2.1): 过流 -> 锁存到手动解除; 欠压 -> 自动恢复.
 * 运行中欠压按新电压样本连续确认 UVP_CONFIRM_MS, 正常样本清零计时;
 * 合闸后 PROT_BLANK_MS 内仅屏蔽过流, 欠压确认照常计时;
 * 过流只在新样本上判定, 需持续 OCP_CONFIRM_MS 才锁存, 负载瞬变/尖峰不会误触发 */
static void App_ProtectionCheck(void)
{
  if ((appState == APP_ST_CV) || (appState == APP_ST_CC))
  {
    if (vinFresh != 0U)
    {
      vinFresh = 0U;
      if ((uvpIgnored == 0U) && (measVin < UVP_TRIP_V))
      {
        if (uvpTracking == 0U)
        {
          uvpTracking = 1U;
          uvpSince = HAL_GetTick();
        }
        else if ((uint32_t)(HAL_GetTick() - uvpSince) >= UVP_CONFIRM_MS)
        {
          App_SetState(APP_ST_PROT_UVP);
          return;
        }
      }
      else
      {
        uvpTracking = 0U;
      }
    }
    if ((int32_t)(HAL_GetTick() - protBlankUntil) < 0)
    {
      return;                                 /* 屏蔽期内 */
    }

    /* 过流确认: 任一"正常"的新样本立即清零累计, 只认持续过流 */
    if (ioutFresh != 0U)
    {
      ioutFresh = 0U;
      if (measIout > OCP_TRIP_A)
      {
        if (ocpTracking == 0U)
        {
          ocpTracking = 1U;
          ocpSince = HAL_GetTick();
        }
        else if ((uint32_t)(HAL_GetTick() - ocpSince) >= OCP_CONFIRM_MS)
        {
          App_SetState(APP_ST_PROT_OCP);
          return;
        }
      }
      else
      {
        ocpTracking = 0U;
      }
    }

  }
  else
  {
    /* 待机及保护状态不自动合闸; 欠压即使恢复正常也等待 K3 短按确认. */
  }
}

static char *App_StateText(AppState_t st)
{
  switch (st)
  {
    case APP_ST_SELF_TEST: return "SELF TEST";
    case APP_ST_STANDBY:   return "STANDBY";
    case APP_ST_CV:        return "CV MODE";
    case APP_ST_CC:        return "CC MODE";
    case APP_ST_PROT_OCP:  return "OCP ALARM!";
    case APP_ST_PROT_UVP:  return "UVP ALARM!";
    case APP_ST_PROT_ADC:  return "ADC FAULT!";
    default:               return "?";
  }
}

/* 显示平滑: 把当前测量值压入窗口, 返回最近 DISPLAY_AVG_TICKS 次的平均.
 * 仅用于屏幕显示; 保护判断仍用实时 meas* 值, 不增加保护延迟.
 * 首次调用/状态切换后用当前值填满窗口, 避免从 0 或旧值慢慢爬升. */
static void App_DisplayAverage(float *vin, float *vout, float *iin, float *iout)
{
  float vals[4];
  float sum[4] = {0.0f, 0.0f, 0.0f, 0.0f};
  uint8_t ch;
  uint8_t k;

  vals[0] = measVin;
  vals[1] = measVout;
  vals[2] = measIin;
  vals[3] = measIout;

  if (dispHistFilled == 0U)
  {
    for (ch = 0U; ch < 4U; ch++)
    {
      for (k = 0U; k < DISPLAY_AVG_TICKS; k++)
      {
        dispHist[ch][k] = vals[ch];
      }
    }
    dispHistFilled = DISPLAY_AVG_TICKS;
    dispHistIdx = 0U;
  }
  else
  {
    for (ch = 0U; ch < 4U; ch++)
    {
      dispHist[ch][dispHistIdx] = vals[ch];
    }
    dispHistIdx = (uint8_t)((dispHistIdx + 1U) % DISPLAY_AVG_TICKS);
    if (dispHistFilled < DISPLAY_AVG_TICKS)
    {
      dispHistFilled++;
    }
  }

  for (ch = 0U; ch < 4U; ch++)
  {
    for (k = 0U; k < dispHistFilled; k++)
    {
      sum[ch] += dispHist[ch][k];
    }
    sum[ch] /= (float)dispHistFilled;
  }

  *vin  = sum[0];
  *vout = sum[1];
  *iin  = sum[2];
  *iout = sum[3];
}

/* 屏幕布局 (6×8 字体, 行距 8px):
 *   y=0  "Power Manager" 固定标题 (题目 1.1)
 *   y=8  工作状态
 *   y=16 Vin / y=24 Vout / y=32 Iin / y=40 Iout   四个测量值 (题目 1.7)
 *   y=48 设定值 (恒压=目标电压, 恒流=目标电流)
 *   y=56 按键操作提示 */
static void App_UpdateDisplay(void)
{
  char *hint;
  float voutDisp;
  float dispVin;
  float dispVout;
  float dispIin;
  float dispIout;

  /* 显示平滑: 取最近 DISPLAY_AVG_TICKS 次刷新的平均, 抑制末位跳动 */
  App_DisplayAverage(&dispVin, &dispVout, &dispIin, &dispIout);

  OLED_Clear();
  OLED_ShowString(0, 0,  "Power Manager", OLED_FONT);
  OLED_ShowString(0, 8,  App_StateText(appState), OLED_FONT);

  OLED_ShowString(0, 16, "Vin", OLED_FONT);
  OLED_ShowFloatNum(OLED_VALUE_X, 16, dispVin, OLED_FLOAT_INT_LEN, OLED_FLOAT_FRA_LEN, OLED_FONT);
  OLED_ShowChar(OLED_UNIT_X, 16, 'V', OLED_FONT);

  /* PA6 采的是输出正端对系统地; Q3 在负端, 关断时负端浮空.
     非运行状态的 0.00V 代表输出已禁用, 并非实测端子压差;
     正端仍可能带电. 运行读数已按实测电流补偿为端子电压估计值. */
  voutDisp = ((appState == APP_ST_CV) || (appState == APP_ST_CC)) ? dispVout : 0.0f;
  OLED_ShowString(0, 24, "Vout", OLED_FONT);
  OLED_ShowFloatNum(OLED_VALUE_X, 24, voutDisp, OLED_FLOAT_INT_LEN, OLED_FLOAT_FRA_LEN, OLED_FONT);
  OLED_ShowChar(OLED_UNIT_X, 24, 'V', OLED_FONT);

  OLED_ShowString(0, 32, "Iin", OLED_FONT);
  OLED_ShowFloatNum(OLED_VALUE_X, 32, dispIin, OLED_FLOAT_INT_LEN, OLED_FLOAT_FRA_LEN, OLED_FONT);
  OLED_ShowChar(OLED_UNIT_X, 32, 'A', OLED_FONT);

  OLED_ShowString(0, 40, "Iout", OLED_FONT);
  OLED_ShowFloatNum(OLED_VALUE_X, 40, dispIout, OLED_FLOAT_INT_LEN, OLED_FLOAT_FRA_LEN, OLED_FONT);
  OLED_ShowChar(OLED_UNIT_X, 40, 'A', OLED_FONT);

  OLED_ShowString(0, 48, "Set", OLED_FONT);
  if (appState == APP_ST_CC)
  {
    OLED_ShowFloatNum(OLED_VALUE_X, 48, targetI, OLED_FLOAT_INT_LEN, OLED_FLOAT_FRA_LEN, OLED_FONT);
    OLED_ShowChar(OLED_UNIT_X, 48, 'A', OLED_FONT);
  }
  else
  {
    OLED_ShowFloatNum(OLED_VALUE_X, 48, targetV, OLED_FLOAT_INT_LEN, OLED_FLOAT_FRA_LEN, OLED_FONT);
    OLED_ShowChar(OLED_UNIT_X, 48, 'V', OLED_FONT);
  }

  switch (appState)
  {
    case APP_ST_STANDBY:   hint = "K3=START"; break;
    case APP_ST_CV:        hint = "K1/K2=ADJ HOLD K3=CC"; break;
    case APP_ST_CC:        hint = "K1/K2=ADJ HOLD K3=CV"; break;
    case APP_ST_PROT_OCP:  hint = "K3=CLEAR"; break;
    case APP_ST_PROT_UVP:  hint = "K3=IGNORE"; break;
    case APP_ST_PROT_ADC:  hint = "K3=RETRY TO STANDBY"; break;
    default:               hint = ""; break;
  }
  OLED_ShowString(0, 56, hint, OLED_FONT);

  OLED_Update();
}
/* USER CODE END 4 */

void Error_Handler(void)
{
  /* USER CODE BEGIN Error_Handler_Debug */
  /* HAL 初始化或 DAC 写入失败也应先断输出, 防止停在带电状态. */
  App_OutputEnable(0U);
  App_Buzzer(1U);
  /* User can add his own implementation to report the HAL error return state */
  __disable_irq();
  while (1)
  {
  }
  /* USER CODE END Error_Handler_Debug */
}
